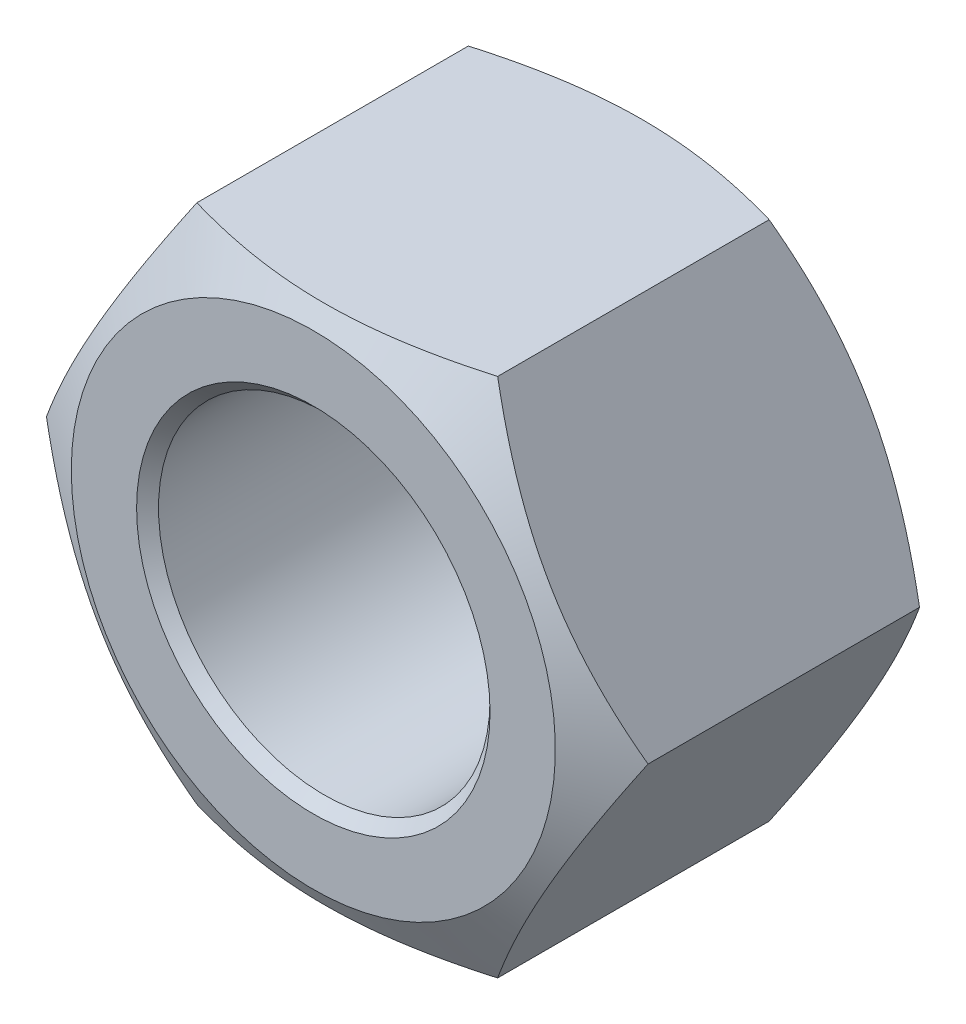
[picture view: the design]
ISO-10303-21;
HEADER;
FILE_DESCRIPTION(('STEP AP214'),'2;1');
FILE_NAME('part.step','',(''),(''),'','','');
FILE_SCHEMA(('AUTOMOTIVE_DESIGN { 1 0 10303 214 1 1 1 1 }'));
ENDSEC;
DATA;
#1=APPLICATION_CONTEXT('core data for automotive mechanical design processes');
#2=APPLICATION_PROTOCOL_DEFINITION('international standard','automotive_design',2000,#1);
#3=PRODUCT_CONTEXT('',#1,'mechanical');
#4=PRODUCT('Part','Part','',(#3));
#5=PRODUCT_RELATED_PRODUCT_CATEGORY('part','',(#4));
#6=PRODUCT_DEFINITION_FORMATION('','',#4);
#7=PRODUCT_DEFINITION_CONTEXT('part definition',#1,'design');
#8=PRODUCT_DEFINITION('design','',#6,#7);
#9=PRODUCT_DEFINITION_SHAPE('','',#8);
#10=(LENGTH_UNIT() NAMED_UNIT(*) SI_UNIT(.MILLI.,.METRE.));
#11=(NAMED_UNIT(*) PLANE_ANGLE_UNIT() SI_UNIT($,.RADIAN.));
#12=(NAMED_UNIT(*) SI_UNIT($,.STERADIAN.) SOLID_ANGLE_UNIT());
#13=UNCERTAINTY_MEASURE_WITH_UNIT(LENGTH_MEASURE(1.E-05),#10,'distance_accuracy_value','');
#14=(GEOMETRIC_REPRESENTATION_CONTEXT(3) GLOBAL_UNCERTAINTY_ASSIGNED_CONTEXT((#13)) GLOBAL_UNIT_ASSIGNED_CONTEXT((#10,
#11,#12)) REPRESENTATION_CONTEXT('',''));
#15=CARTESIAN_POINT('',(0.,0.,0.));
#16=DIRECTION('',(0.,0.,1.));
#17=DIRECTION('',(1.,0.,0.));
#18=AXIS2_PLACEMENT_3D('',#15,#16,#17);
#19=CARTESIAN_POINT('',(-15.8771324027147,-27.5,-34.7));
#20=DIRECTION('',(0.,-1.,0.));
#21=DIRECTION('',(1.,0.,0.));
#22=AXIS2_PLACEMENT_3D('',#19,#20,#21);
#23=PLANE('',#22);
#24=DIRECTION('',(0.,0.,1.));
#25=VECTOR('',#24,1.);
#26=CARTESIAN_POINT('',(15.8771324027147,-27.5,-34.7));
#27=LINE('',#26,#25);
#28=CARTESIAN_POINT('',(15.8771324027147,-27.5,-32.2437990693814));
#29=VERTEX_POINT('',#28);
#30=CARTESIAN_POINT('',(15.8771324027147,-27.5,-3.58203395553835));
#31=VERTEX_POINT('',#30);
#32=EDGE_CURVE('E149',#29,#31,#27,.T.);
#33=ORIENTED_EDGE('',*,*,#32,.T.);
#34=CARTESIAN_POINT('',(-41.9525411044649,-27.5,-14.2099719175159));
#35=CARTESIAN_POINT('',(-41.3494641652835,-27.5,-13.9187804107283));
#36=CARTESIAN_POINT('',(-40.7456533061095,-27.5,-13.6291040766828));
#37=CARTESIAN_POINT('',(-39.5364097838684,-27.5,-13.0531398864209));
#38=CARTESIAN_POINT('',(-38.9309771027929,-27.5,-12.7668520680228));
#39=CARTESIAN_POINT('',(-37.718245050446,-27.5,-12.19798059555));
#40=CARTESIAN_POINT('',(-37.1109453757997,-27.5,-11.9153975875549));
#41=CARTESIAN_POINT('',(-35.8944183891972,-27.5,-11.3544179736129));
#42=CARTESIAN_POINT('',(-35.2851910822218,-27.5,-11.0760213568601));
#43=CARTESIAN_POINT('',(-33.4472762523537,-27.5,-10.2446151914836));
#44=CARTESIAN_POINT('',(-32.2153690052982,-27.5,-9.69869201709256));
#45=CARTESIAN_POINT('',(-29.7413669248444,-27.5,-8.63048780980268));
#46=CARTESIAN_POINT('',(-28.4992726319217,-27.5,-8.10820553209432));
#47=CARTESIAN_POINT('',(-26.6196585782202,-27.5,-7.34437012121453));
#48=CARTESIAN_POINT('',(-25.9866820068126,-27.5,-7.09162545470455));
#49=CARTESIAN_POINT('',(-24.717313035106,-27.5,-6.59487593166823));
#50=CARTESIAN_POINT('',(-24.0809206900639,-27.5,-6.35087093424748));
#51=CARTESIAN_POINT('',(-22.804327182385,-27.5,-5.87272698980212));
#52=CARTESIAN_POINT('',(-22.1641254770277,-27.5,-5.63858948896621));
#53=CARTESIAN_POINT('',(-20.8797293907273,-27.5,-5.18156563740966));
#54=CARTESIAN_POINT('',(-20.2355351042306,-27.5,-4.95867902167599));
#55=CARTESIAN_POINT('',(-18.9442516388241,-27.5,-4.52613766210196));
#56=CARTESIAN_POINT('',(-18.2971717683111,-27.5,-4.31645526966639));
#57=CARTESIAN_POINT('',(-16.9985288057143,-27.5,-3.91151041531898));
#58=CARTESIAN_POINT('',(-16.3469656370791,-27.5,-3.71624820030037));
#59=CARTESIAN_POINT('',(-14.3855682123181,-27.5,-3.15498057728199));
#60=CARTESIAN_POINT('',(-13.0685242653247,-27.5,-2.81332315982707));
#61=CARTESIAN_POINT('',(-11.078834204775,-27.5,-2.36222983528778));
#62=CARTESIAN_POINT('',(-10.413074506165,-27.5,-2.22206895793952));
#63=CARTESIAN_POINT('',(-9.07715007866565,-27.5,-1.96444454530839));
#64=CARTESIAN_POINT('',(-8.40698545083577,-27.5,-1.84698049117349));
#65=CARTESIAN_POINT('',(-7.06271975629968,-27.5,-1.63684108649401));
#66=CARTESIAN_POINT('',(-6.3886184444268,-27.5,-1.54416729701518));
#67=CARTESIAN_POINT('',(-5.03726233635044,-27.5,-1.38547485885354));
#68=CARTESIAN_POINT('',(-4.36000753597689,-27.5,-1.31945624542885));
#69=CARTESIAN_POINT('',(-3.00754087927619,-27.5,-1.2158431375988));
#70=CARTESIAN_POINT('',(-2.33234242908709,-27.5,-1.17807478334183));
#71=CARTESIAN_POINT('',(-0.980955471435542,-27.5,-1.13115834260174));
#72=CARTESIAN_POINT('',(-0.30476697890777,-27.5,-1.1220098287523));
#73=CARTESIAN_POINT('',(1.04720420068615,-27.5,-1.13254920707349));
#74=CARTESIAN_POINT('',(1.72298694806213,-27.5,-1.15222928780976));
#75=CARTESIAN_POINT('',(3.07313517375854,-27.5,-1.21994143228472));
#76=CARTESIAN_POINT('',(3.7475005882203,-27.5,-1.26797474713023));
#77=CARTESIAN_POINT('',(5.38649088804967,-27.5,-1.41817622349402));
#78=CARTESIAN_POINT('',(6.34981216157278,-27.5,-1.53480225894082));
#79=CARTESIAN_POINT('',(8.26885266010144,-27.5,-1.81938601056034));
#80=CARTESIAN_POINT('',(9.22457071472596,-27.5,-1.98735147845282));
#81=CARTESIAN_POINT('',(11.1289249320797,-27.5,-2.36889784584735));
#82=CARTESIAN_POINT('',(12.0775412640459,-27.5,-2.58257679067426));
#83=CARTESIAN_POINT('',(13.9650122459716,-27.5,-3.04892276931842));
#84=CARTESIAN_POINT('',(14.9038672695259,-27.5,-3.30158830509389));
#85=CARTESIAN_POINT('',(16.7937069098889,-27.5,-3.84612374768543));
#86=CARTESIAN_POINT('',(17.7444669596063,-27.5,-4.13876776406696));
#87=CARTESIAN_POINT('',(19.6366730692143,-27.5,-4.75285886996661));
#88=CARTESIAN_POINT('',(20.5781182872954,-27.5,-5.07430853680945));
#89=CARTESIAN_POINT('',(22.4471611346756,-27.5,-5.73923774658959));
#90=CARTESIAN_POINT('',(23.374806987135,-27.5,-6.08258225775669));
#91=CARTESIAN_POINT('',(24.7604452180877,-27.5,-6.61229984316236));
#92=CARTESIAN_POINT('',(25.2212799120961,-27.5,-6.79129281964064));
#93=CARTESIAN_POINT('',(26.1411616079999,-27.5,-7.15377962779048));
#94=CARTESIAN_POINT('',(26.6002086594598,-27.5,-7.33727333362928));
#95=CARTESIAN_POINT('',(27.0584275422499,-27.5,-7.52281490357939));
#96=B_SPLINE_CURVE_WITH_KNOTS('',3,(#34,#35,#36,#37,#38,#39,#40,#41,#42,#43,#44,#45,#46,#47,#48,
#49,#50,#51,#52,#53,#54,#55,#56,#57,#58,#59,#60,#61,#62,#63,#64,#65,#66,#67,#68,#69,#70,#71,#72,
#73,#74,#75,#76,#77,#78,#79,#80,#81,#82,#83,#84,#85,#86,#87,#88,#89,#90,#91,#92,#93,#94,#95),
.UNSPECIFIED.,.F.,.F.,(4,2,2,2,2,2,2,2,2,2,2,2,2,2,2,2,2,2,2,2,2,2,2,2,2,2,2,2,2,2,4),(0.,
2.00909235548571,4.01820711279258,6.02766769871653,8.03712309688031,12.0792874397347,
16.1212386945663,18.1658995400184,20.2105274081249,22.2554539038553,24.3003322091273,
26.3407756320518,28.3812539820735,32.4606217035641,34.5013713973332,36.5420744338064,
38.5829059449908,40.6237401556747,42.651908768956,44.680047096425,46.7076359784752,
48.7353143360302,51.6447569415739,54.5546390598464,57.4708259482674,60.3869008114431,
63.3706883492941,66.3547431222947,69.3219029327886,70.8050103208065,72.288076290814),.UNSPECIFIED.);
#97=CARTESIAN_POINT('',(-15.8771324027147,-27.5,-3.58203395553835));
#98=VERTEX_POINT('',#97);
#99=EDGE_CURVE('E57',#31,#98,#96,.F.);
#100=ORIENTED_EDGE('',*,*,#99,.T.);
#101=DIRECTION('',(0.,0.,1.));
#102=VECTOR('',#101,1.);
#103=CARTESIAN_POINT('',(-15.8771324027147,-27.5,-34.7));
#104=LINE('',#103,#102);
#105=CARTESIAN_POINT('',(-15.8771324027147,-27.5,-32.2437990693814));
#106=VERTEX_POINT('',#105);
#107=EDGE_CURVE('E127',#106,#98,#104,.T.);
#108=ORIENTED_EDGE('',*,*,#107,.F.);
#109=CARTESIAN_POINT('',(-42.108494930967,-27.5,-21.5405156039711));
#110=CARTESIAN_POINT('',(-41.5048149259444,-27.5,-21.8323227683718));
#111=CARTESIAN_POINT('',(-40.9004047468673,-27.5,-22.1226241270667));
#112=CARTESIAN_POINT('',(-39.6899708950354,-27.5,-22.6998596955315));
#113=CARTESIAN_POINT('',(-39.0839472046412,-27.5,-22.9867938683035));
#114=CARTESIAN_POINT('',(-37.8700434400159,-27.5,-23.5569814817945));
#115=CARTESIAN_POINT('',(-37.2621630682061,-27.5,-23.840234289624));
#116=CARTESIAN_POINT('',(-36.0444843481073,-27.5,-24.4025807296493));
#117=CARTESIAN_POINT('',(-35.4346860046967,-27.5,-24.6816743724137));
#118=CARTESIAN_POINT('',(-33.5951504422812,-27.5,-25.5151881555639));
#119=CARTESIAN_POINT('',(-32.3622101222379,-27.5,-26.0625698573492));
#120=CARTESIAN_POINT('',(-29.8861914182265,-27.5,-27.1338541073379));
#121=CARTESIAN_POINT('',(-28.6431135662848,-27.5,-27.6577578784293));
#122=CARTESIAN_POINT('',(-26.761690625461,-27.5,-28.4243433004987));
#123=CARTESIAN_POINT('',(-26.1278670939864,-27.5,-28.6781337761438));
#124=CARTESIAN_POINT('',(-24.856813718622,-27.5,-29.177025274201));
#125=CARTESIAN_POINT('',(-24.2195839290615,-27.5,-29.4221264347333));
#126=CARTESIAN_POINT('',(-22.9413245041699,-27.5,-29.9025185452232));
#127=CARTESIAN_POINT('',(-22.3002943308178,-27.5,-30.1378080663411));
#128=CARTESIAN_POINT('',(-21.0142476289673,-27.5,-30.5971975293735));
#129=CARTESIAN_POINT('',(-20.3692311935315,-27.5,-30.8212977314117));
#130=CARTESIAN_POINT('',(-19.0762913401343,-27.5,-31.256336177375));
#131=CARTESIAN_POINT('',(-18.4283771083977,-27.5,-31.4673015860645));
#132=CARTESIAN_POINT('',(-17.1280636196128,-27.5,-31.874881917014));
#133=CARTESIAN_POINT('',(-16.4756642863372,-27.5,-32.0714965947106));
#134=CARTESIAN_POINT('',(-14.5117448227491,-27.5,-32.6369304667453));
#135=CARTESIAN_POINT('',(-13.1930050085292,-27.5,-32.9815100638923));
#136=CARTESIAN_POINT('',(-11.2007577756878,-27.5,-33.4371656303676));
#137=CARTESIAN_POINT('',(-10.5341776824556,-27.5,-33.5788718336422));
#138=CARTESIAN_POINT('',(-9.19657522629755,-27.5,-33.8396423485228));
#139=CARTESIAN_POINT('',(-8.52555296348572,-27.5,-33.9587071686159));
#140=CARTESIAN_POINT('',(-7.17952384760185,-27.5,-34.1720839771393));
#141=CARTESIAN_POINT('',(-6.50451675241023,-27.5,-34.2663944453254));
#142=CARTESIAN_POINT('',(-5.15128946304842,-27.5,-34.4283683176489));
#143=CARTESIAN_POINT('',(-4.47306926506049,-27.5,-34.4960316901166));
#144=CARTESIAN_POINT('',(-3.11871087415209,-27.5,-34.6028897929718));
#145=CARTESIAN_POINT('',(-2.44258682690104,-27.5,-34.6422626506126));
#146=CARTESIAN_POINT('',(-1.08928096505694,-27.5,-34.6923327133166));
#147=CARTESIAN_POINT('',(-0.412099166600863,-27.5,-34.7030303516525));
#148=CARTESIAN_POINT('',(0.941918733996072,-27.5,-34.6954963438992));
#149=CARTESIAN_POINT('',(1.61875487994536,-27.5,-34.6772727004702));
#150=CARTESIAN_POINT('',(2.97106504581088,-27.5,-34.6123489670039));
#151=CARTESIAN_POINT('',(3.64653900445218,-27.5,-34.5656476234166));
#152=CARTESIAN_POINT('',(5.28317631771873,-27.5,-34.4189661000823));
#153=CARTESIAN_POINT('',(6.24308439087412,-27.5,-34.3047469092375));
#154=CARTESIAN_POINT('',(8.15543073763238,-27.5,-34.0251507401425));
#155=CARTESIAN_POINT('',(9.10786788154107,-27.5,-33.8597661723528));
#156=CARTESIAN_POINT('',(11.0057578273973,-27.5,-33.4834652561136));
#157=CARTESIAN_POINT('',(11.9511910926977,-27.5,-33.2724513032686));
#158=CARTESIAN_POINT('',(13.8323781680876,-27.5,-32.8114440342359));
#159=CARTESIAN_POINT('',(14.7681323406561,-27.5,-32.5614521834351));
#160=CARTESIAN_POINT('',(16.6519981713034,-27.5,-32.0222222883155));
#161=CARTESIAN_POINT('',(17.5998839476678,-27.5,-31.7322004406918));
#162=CARTESIAN_POINT('',(19.4863693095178,-27.5,-31.1232820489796));
#163=CARTESIAN_POINT('',(20.4249680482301,-27.5,-30.8043828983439));
#164=CARTESIAN_POINT('',(22.2883658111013,-27.5,-30.1444557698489));
#165=CARTESIAN_POINT('',(23.2132128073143,-27.5,-29.8035627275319));
#166=CARTESIAN_POINT('',(24.5946517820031,-27.5,-29.2774659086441));
#167=CARTESIAN_POINT('',(25.054086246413,-27.5,-29.0996704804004));
#168=CARTESIAN_POINT('',(25.9711665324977,-27.5,-28.7395606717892));
#169=CARTESIAN_POINT('',(26.4288124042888,-27.5,-28.5572464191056));
#170=CARTESIAN_POINT('',(26.8856293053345,-27.5,-28.3728755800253));
#171=B_SPLINE_CURVE_WITH_KNOTS('',3,(#109,#110,#111,#112,#113,#114,#115,#116,#117,#118,#119,
#120,#121,#122,#123,#124,#125,#126,#127,#128,#129,#130,#131,#132,#133,#134,#135,#136,#137,#138,
#139,#140,#141,#142,#143,#144,#145,#146,#147,#148,#149,#150,#151,#152,#153,#154,#155,#156,#157,
#158,#159,#160,#161,#162,#163,#164,#165,#166,#167,#168,#169,#170),.UNSPECIFIED.,.F.,.F.,(4,2,2,
2,2,2,2,2,2,2,2,2,2,2,2,2,2,2,2,2,2,2,2,2,2,2,2,2,2,2,4),(0.,2.01152483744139,4.02307175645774,
6.034960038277,8.0468432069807,12.0936174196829,16.1401806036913,18.1883662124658,
20.2365192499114,22.2849695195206,24.3333721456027,26.3773870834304,28.42143684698,
32.5079579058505,34.5520769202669,36.596150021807,38.6403486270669,40.6845496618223,
42.7157641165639,44.7469478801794,46.7775697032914,48.808280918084,51.7067063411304,
54.6055619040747,57.5106807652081,60.4156904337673,63.3889230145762,66.3624242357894,
69.3191566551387,70.7970485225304,72.2748986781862),.UNSPECIFIED.);
#172=CARTESIAN_POINT('',(0.,-27.5,-34.7));
#173=VERTEX_POINT('',#172);
#174=EDGE_CURVE('E313',#106,#173,#171,.T.);
#175=ORIENTED_EDGE('',*,*,#174,.T.);
#176=EDGE_CURVE('E174',#173,#29,#171,.T.);
#177=ORIENTED_EDGE('',*,*,#176,.T.);
#178=EDGE_LOOP('',(#33,#100,#108,#175,#177));
#179=FACE_BOUND('',#178,.T.);
#180=ADVANCED_FACE('F41',(#179),#23,.T.);
#181=CARTESIAN_POINT('',(-31.7542648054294,0.,-34.7));
#182=DIRECTION('',(-0.866025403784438,-0.5,0.));
#183=DIRECTION('',(0.5,-0.866025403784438,0.));
#184=AXIS2_PLACEMENT_3D('',#181,#182,#183);
#185=PLANE('',#184);
#186=ORIENTED_EDGE('',*,*,#107,.T.);
#187=CARTESIAN_POINT('',(-15.8770169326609,-27.5002,-3.58210062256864));
#188=CARTESIAN_POINT('',(-16.2259892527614,-26.8957622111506,-3.38063638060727));
#189=CARTESIAN_POINT('',(-16.5763227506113,-26.2889667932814,-3.1883143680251));
#190=CARTESIAN_POINT('',(-17.2797989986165,-25.0705101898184,-2.82449599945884));
#191=CARTESIAN_POINT('',(-17.6329426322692,-24.4588474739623,-2.65300649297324));
#192=CARTESIAN_POINT('',(-18.3427291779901,-23.229461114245,-2.33315493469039));
#193=CARTESIAN_POINT('',(-18.6993783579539,-22.6117266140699,-2.18484811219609));
#194=CARTESIAN_POINT('',(-19.4151397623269,-21.371991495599,-1.91455679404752));
#195=CARTESIAN_POINT('',(-19.7742517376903,-20.7499913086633,-1.79256967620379));
#196=CARTESIAN_POINT('',(-20.4857595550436,-19.5176236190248,-1.58009593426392));
#197=CARTESIAN_POINT('',(-20.8381026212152,-18.907347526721,-1.48890665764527));
#198=CARTESIAN_POINT('',(-21.5444032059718,-17.683999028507,-1.33600321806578));
#199=CARTESIAN_POINT('',(-21.8983607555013,-17.0709265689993,-1.27428962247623));
#200=CARTESIAN_POINT('',(-22.6068704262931,-15.8437518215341,-1.181895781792));
#201=CARTESIAN_POINT('',(-22.9614213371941,-15.2296516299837,-1.15117866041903));
#202=CARTESIAN_POINT('',(-23.6708503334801,-14.0008845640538,-1.12143833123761));
#203=CARTESIAN_POINT('',(-24.025728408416,-13.3862177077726,-1.12241414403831));
#204=CARTESIAN_POINT('',(-24.6891773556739,-12.2370904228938,-1.15384594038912));
#205=CARTESIAN_POINT('',(-24.9977954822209,-11.7025481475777,-1.180469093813));
#206=CARTESIAN_POINT('',(-25.6142949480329,-10.6347397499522,-1.25717911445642));
#207=CARTESIAN_POINT('',(-25.9221762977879,-10.1014736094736,-1.30726564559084));
#208=CARTESIAN_POINT('',(-26.5370884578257,-9.03641450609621,-1.43003437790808));
#209=CARTESIAN_POINT('',(-26.8441182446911,-8.50462331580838,-1.50273701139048));
#210=CARTESIAN_POINT('',(-27.4567077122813,-7.44358723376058,-1.6694512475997));
#211=CARTESIAN_POINT('',(-27.7622673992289,-6.9143423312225,-1.76346276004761));
#212=CARTESIAN_POINT('',(-28.6898814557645,-5.30766765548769,-2.07987326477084));
#213=CARTESIAN_POINT('',(-29.3093003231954,-4.23480270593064,-2.33383899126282));
#214=CARTESIAN_POINT('',(-30.2315881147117,-2.63735339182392,-2.76620358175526));
#215=CARTESIAN_POINT('',(-30.5376130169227,-2.10730271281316,-2.91873886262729));
#216=CARTESIAN_POINT('',(-31.1475461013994,-1.05086762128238,-3.23925171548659));
#217=CARTESIAN_POINT('',(-31.4514548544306,-0.524482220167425,-3.40722493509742));
#218=CARTESIAN_POINT('',(-31.7543802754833,0.000199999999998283,-3.58210062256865));
#219=B_SPLINE_CURVE_WITH_KNOTS('',3,(#187,#188,#189,#190,#191,#192,#193,#194,#195,#196,#197,
#198,#199,#200,#201,#202,#203,#204,#205,#206,#207,#208,#209,#210,#211,#212,#213,#214,#215,#216,
#217,#218),.UNSPECIFIED.,.F.,.F.,(4,2,2,2,2,2,2,2,2,2,2,2,2,2,2,4),(0.,2.17937596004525,
4.35946654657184,6.54467421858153,8.72966408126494,10.8607692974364,12.9919155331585,
15.120523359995,17.2490654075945,19.1020483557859,20.9550047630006,22.8096400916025,
24.6642675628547,28.4552152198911,30.3473870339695,32.2390270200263),.UNSPECIFIED.);
#220=CARTESIAN_POINT('',(-31.7542648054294,0.,-3.58203395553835));
#221=VERTEX_POINT('',#220);
#222=EDGE_CURVE('E112',#98,#221,#219,.T.);
#223=ORIENTED_EDGE('',*,*,#222,.T.);
#224=DIRECTION('',(0.,0.,1.));
#225=VECTOR('',#224,1.);
#226=CARTESIAN_POINT('',(-31.7542648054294,0.,-34.7));
#227=LINE('',#226,#225);
#228=CARTESIAN_POINT('',(-31.7542648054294,0.,-32.2437990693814));
#229=VERTEX_POINT('',#228);
#230=EDGE_CURVE('E130',#229,#221,#227,.T.);
#231=ORIENTED_EDGE('',*,*,#230,.F.);
#232=CARTESIAN_POINT('',(-31.7543802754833,0.000200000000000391,-32.2437324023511));
#233=CARTESIAN_POINT('',(-31.4054079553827,-0.604237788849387,-32.4451966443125));
#234=CARTESIAN_POINT('',(-31.0550744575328,-1.21103320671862,-32.6375186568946));
#235=CARTESIAN_POINT('',(-30.3515982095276,-2.42948981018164,-33.0013370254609));
#236=CARTESIAN_POINT('',(-29.9984545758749,-3.04115252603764,-33.1728265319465));
#237=CARTESIAN_POINT('',(-29.288668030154,-4.27053888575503,-33.4926780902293));
#238=CARTESIAN_POINT('',(-28.9320188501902,-4.88827338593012,-33.6409849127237));
#239=CARTESIAN_POINT('',(-28.2162574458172,-6.12800850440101,-33.9112762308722));
#240=CARTESIAN_POINT('',(-27.8571454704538,-6.75000869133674,-34.033263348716));
#241=CARTESIAN_POINT('',(-27.1456376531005,-7.98237638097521,-34.2457370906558));
#242=CARTESIAN_POINT('',(-26.7932945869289,-8.59265247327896,-34.3369263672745));
#243=CARTESIAN_POINT('',(-26.0869940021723,-9.81600097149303,-34.489829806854));
#244=CARTESIAN_POINT('',(-25.7330364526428,-10.4290734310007,-34.5515434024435));
#245=CARTESIAN_POINT('',(-25.024526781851,-11.6562481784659,-34.6439372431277));
#246=CARTESIAN_POINT('',(-24.66997587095,-12.2703483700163,-34.6746543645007));
#247=CARTESIAN_POINT('',(-23.960546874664,-13.4991154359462,-34.7043946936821));
#248=CARTESIAN_POINT('',(-23.6056687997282,-14.1137822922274,-34.7034188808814));
#249=CARTESIAN_POINT('',(-22.9422198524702,-15.2629095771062,-34.6719870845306));
#250=CARTESIAN_POINT('',(-22.6336017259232,-15.7974518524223,-34.6453639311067));
#251=CARTESIAN_POINT('',(-22.0171022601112,-16.8652602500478,-34.5686539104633));
#252=CARTESIAN_POINT('',(-21.7092209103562,-17.3985263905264,-34.5185673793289));
#253=CARTESIAN_POINT('',(-21.0943087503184,-18.4635854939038,-34.3957986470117));
#254=CARTESIAN_POINT('',(-20.787278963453,-18.9953766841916,-34.3230960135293));
#255=CARTESIAN_POINT('',(-20.1746894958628,-20.0564127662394,-34.15638177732));
#256=CARTESIAN_POINT('',(-19.8691298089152,-20.5856576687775,-34.0623702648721));
#257=CARTESIAN_POINT('',(-18.9415157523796,-22.1923323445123,-33.7459597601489));
#258=CARTESIAN_POINT('',(-18.3220968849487,-23.2651972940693,-33.4919940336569));
#259=CARTESIAN_POINT('',(-17.3998090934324,-24.8626466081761,-33.0596294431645));
#260=CARTESIAN_POINT('',(-17.0937841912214,-25.3926972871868,-32.9070941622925));
#261=CARTESIAN_POINT('',(-16.4838511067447,-26.4491323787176,-32.5865813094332));
#262=CARTESIAN_POINT('',(-16.1799423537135,-26.9755177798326,-32.4186080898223));
#263=CARTESIAN_POINT('',(-15.8770169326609,-27.5002,-32.2437324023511));
#264=B_SPLINE_CURVE_WITH_KNOTS('',3,(#232,#233,#234,#235,#236,#237,#238,#239,#240,#241,#242,
#243,#244,#245,#246,#247,#248,#249,#250,#251,#252,#253,#254,#255,#256,#257,#258,#259,#260,#261,
#262,#263),.UNSPECIFIED.,.F.,.F.,(4,2,2,2,2,2,2,2,2,2,2,2,2,2,2,4),(0.,2.17937596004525,
4.35946654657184,6.54467421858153,8.72966408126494,10.8607692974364,12.9919155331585,
15.120523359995,17.2490654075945,19.1020483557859,20.9550047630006,22.8096400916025,
24.6642675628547,28.4552152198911,30.3473870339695,32.2390270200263),.UNSPECIFIED.);
#265=CARTESIAN_POINT('',(-23.815698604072,-13.75,-34.7));
#266=VERTEX_POINT('',#265);
#267=EDGE_CURVE('E245',#229,#266,#264,.T.);
#268=ORIENTED_EDGE('',*,*,#267,.T.);
#269=EDGE_CURVE('E236',#266,#106,#264,.T.);
#270=ORIENTED_EDGE('',*,*,#269,.T.);
#271=EDGE_LOOP('',(#186,#223,#231,#268,#270));
#272=FACE_BOUND('',#271,.T.);
#273=ADVANCED_FACE('F123',(#272),#185,.T.);
#274=CARTESIAN_POINT('',(-15.8771324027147,27.5,-34.7));
#275=DIRECTION('',(-0.866025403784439,0.5,0.));
#276=DIRECTION('',(-0.5,-0.866025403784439,0.));
#277=AXIS2_PLACEMENT_3D('',#274,#275,#276);
#278=PLANE('',#277);
#279=ORIENTED_EDGE('',*,*,#230,.T.);
#280=CARTESIAN_POINT('',(-31.7543802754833,-0.000199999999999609,-3.58210062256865));
#281=CARTESIAN_POINT('',(-31.4054079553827,0.604237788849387,-3.38063638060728));
#282=CARTESIAN_POINT('',(-31.0550744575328,1.21103320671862,-3.18831436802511));
#283=CARTESIAN_POINT('',(-30.3515982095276,2.42948981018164,-2.82449599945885));
#284=CARTESIAN_POINT('',(-29.9984545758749,3.04115252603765,-2.65300649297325));
#285=CARTESIAN_POINT('',(-29.288668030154,4.27053888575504,-2.3331549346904));
#286=CARTESIAN_POINT('',(-28.9320188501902,4.88827338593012,-2.18484811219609));
#287=CARTESIAN_POINT('',(-28.2162574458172,6.12800850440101,-1.91455679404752));
#288=CARTESIAN_POINT('',(-27.8571454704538,6.75000869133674,-1.79256967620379));
#289=CARTESIAN_POINT('',(-27.1456376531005,7.98237638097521,-1.58009593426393));
#290=CARTESIAN_POINT('',(-26.7932945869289,8.59265247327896,-1.48890665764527));
#291=CARTESIAN_POINT('',(-26.0869940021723,9.81600097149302,-1.33600321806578));
#292=CARTESIAN_POINT('',(-25.7330364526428,10.4290734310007,-1.27428962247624));
#293=CARTESIAN_POINT('',(-25.024526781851,11.6562481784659,-1.181895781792));
#294=CARTESIAN_POINT('',(-24.66997587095,12.2703483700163,-1.15117866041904));
#295=CARTESIAN_POINT('',(-23.960546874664,13.4991154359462,-1.12143833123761));
#296=CARTESIAN_POINT('',(-23.6056687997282,14.1137822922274,-1.12241414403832));
#297=CARTESIAN_POINT('',(-22.9422198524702,15.2629095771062,-1.15384594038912));
#298=CARTESIAN_POINT('',(-22.6336017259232,15.7974518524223,-1.180469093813));
#299=CARTESIAN_POINT('',(-22.0171022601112,16.8652602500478,-1.25717911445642));
#300=CARTESIAN_POINT('',(-21.7092209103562,17.3985263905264,-1.30726564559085));
#301=CARTESIAN_POINT('',(-21.0943087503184,18.4635854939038,-1.43003437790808));
#302=CARTESIAN_POINT('',(-20.787278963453,18.9953766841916,-1.50273701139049));
#303=CARTESIAN_POINT('',(-20.1746894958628,20.0564127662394,-1.6694512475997));
#304=CARTESIAN_POINT('',(-19.8691298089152,20.5856576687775,-1.76346276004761));
#305=CARTESIAN_POINT('',(-18.9415157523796,22.1923323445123,-2.07987326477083));
#306=CARTESIAN_POINT('',(-18.3220968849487,23.2651972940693,-2.33383899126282));
#307=CARTESIAN_POINT('',(-17.3998090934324,24.8626466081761,-2.76620358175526));
#308=CARTESIAN_POINT('',(-17.0937841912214,25.3926972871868,-2.91873886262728));
#309=CARTESIAN_POINT('',(-16.4838511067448,26.4491323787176,-3.23925171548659));
#310=CARTESIAN_POINT('',(-16.1799423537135,26.9755177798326,-3.40722493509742));
#311=CARTESIAN_POINT('',(-15.8770169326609,27.5002,-3.58210062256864));
#312=B_SPLINE_CURVE_WITH_KNOTS('',3,(#280,#281,#282,#283,#284,#285,#286,#287,#288,#289,#290,
#291,#292,#293,#294,#295,#296,#297,#298,#299,#300,#301,#302,#303,#304,#305,#306,#307,#308,#309,
#310,#311),.UNSPECIFIED.,.F.,.F.,(4,2,2,2,2,2,2,2,2,2,2,2,2,2,2,4),(0.,2.17937596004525,
4.35946654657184,6.54467421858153,8.72966408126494,10.8607692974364,12.9919155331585,
15.120523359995,17.2490654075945,19.1020483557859,20.9550047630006,22.8096400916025,
24.6642675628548,28.4552152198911,30.3473870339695,32.2390270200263),.UNSPECIFIED.);
#313=CARTESIAN_POINT('',(-15.8771324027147,27.5,-3.58203395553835));
#314=VERTEX_POINT('',#313);
#315=EDGE_CURVE('E111',#221,#314,#312,.T.);
#316=ORIENTED_EDGE('',*,*,#315,.T.);
#317=DIRECTION('',(0.,0.,1.));
#318=VECTOR('',#317,1.);
#319=CARTESIAN_POINT('',(-15.8771324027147,27.5,-34.7));
#320=LINE('',#319,#318);
#321=CARTESIAN_POINT('',(-15.8771324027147,27.5,-32.2437990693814));
#322=VERTEX_POINT('',#321);
#323=EDGE_CURVE('E138',#322,#314,#320,.T.);
#324=ORIENTED_EDGE('',*,*,#323,.F.);
#325=CARTESIAN_POINT('',(-15.8770169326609,27.5002,-32.2437324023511));
#326=CARTESIAN_POINT('',(-16.2259892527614,26.8957622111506,-32.4451966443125));
#327=CARTESIAN_POINT('',(-16.5763227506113,26.2889667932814,-32.6375186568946));
#328=CARTESIAN_POINT('',(-17.2797989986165,25.0705101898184,-33.0013370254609));
#329=CARTESIAN_POINT('',(-17.6329426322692,24.4588474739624,-33.1728265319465));
#330=CARTESIAN_POINT('',(-18.3427291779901,23.229461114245,-33.4926780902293));
#331=CARTESIAN_POINT('',(-18.6993783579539,22.6117266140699,-33.6409849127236));
#332=CARTESIAN_POINT('',(-19.4151397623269,21.371991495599,-33.9112762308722));
#333=CARTESIAN_POINT('',(-19.7742517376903,20.7499913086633,-34.033263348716));
#334=CARTESIAN_POINT('',(-20.4857595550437,19.5176236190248,-34.2457370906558));
#335=CARTESIAN_POINT('',(-20.8381026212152,18.907347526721,-34.3369263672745));
#336=CARTESIAN_POINT('',(-21.5444032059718,17.683999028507,-34.489829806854));
#337=CARTESIAN_POINT('',(-21.8983607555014,17.0709265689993,-34.5515434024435));
#338=CARTESIAN_POINT('',(-22.6068704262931,15.8437518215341,-34.6439372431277));
#339=CARTESIAN_POINT('',(-22.9614213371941,15.2296516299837,-34.6746543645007));
#340=CARTESIAN_POINT('',(-23.6708503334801,14.0008845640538,-34.7043946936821));
#341=CARTESIAN_POINT('',(-24.025728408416,13.3862177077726,-34.7034188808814));
#342=CARTESIAN_POINT('',(-24.6891773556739,12.2370904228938,-34.6719870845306));
#343=CARTESIAN_POINT('',(-24.9977954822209,11.7025481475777,-34.6453639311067));
#344=CARTESIAN_POINT('',(-25.6142949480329,10.6347397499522,-34.5686539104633));
#345=CARTESIAN_POINT('',(-25.9221762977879,10.1014736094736,-34.5185673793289));
#346=CARTESIAN_POINT('',(-26.5370884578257,9.03641450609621,-34.3957986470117));
#347=CARTESIAN_POINT('',(-26.8441182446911,8.50462331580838,-34.3230960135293));
#348=CARTESIAN_POINT('',(-27.4567077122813,7.44358723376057,-34.15638177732));
#349=CARTESIAN_POINT('',(-27.7622673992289,6.91434233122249,-34.0623702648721));
#350=CARTESIAN_POINT('',(-28.6898814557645,5.3076676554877,-33.7459597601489));
#351=CARTESIAN_POINT('',(-29.3093003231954,4.23480270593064,-33.4919940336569));
#352=CARTESIAN_POINT('',(-30.2315881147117,2.63735339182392,-33.0596294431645));
#353=CARTESIAN_POINT('',(-30.5376130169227,2.10730271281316,-32.9070941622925));
#354=CARTESIAN_POINT('',(-31.1475461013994,1.05086762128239,-32.5865813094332));
#355=CARTESIAN_POINT('',(-31.4514548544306,0.524482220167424,-32.4186080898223));
#356=CARTESIAN_POINT('',(-31.7543802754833,-0.000199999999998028,-32.2437324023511));
#357=B_SPLINE_CURVE_WITH_KNOTS('',3,(#325,#326,#327,#328,#329,#330,#331,#332,#333,#334,#335,
#336,#337,#338,#339,#340,#341,#342,#343,#344,#345,#346,#347,#348,#349,#350,#351,#352,#353,#354,
#355,#356),.UNSPECIFIED.,.F.,.F.,(4,2,2,2,2,2,2,2,2,2,2,2,2,2,2,4),(0.,2.17937596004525,
4.35946654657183,6.54467421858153,8.72966408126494,10.8607692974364,12.9919155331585,
15.120523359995,17.2490654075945,19.1020483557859,20.9550047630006,22.8096400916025,
24.6642675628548,28.4552152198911,30.3473870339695,32.2390270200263),.UNSPECIFIED.);
#358=CARTESIAN_POINT('',(-23.8156986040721,13.75,-34.7));
#359=VERTEX_POINT('',#358);
#360=EDGE_CURVE('E154',#322,#359,#357,.T.);
#361=ORIENTED_EDGE('',*,*,#360,.T.);
#362=EDGE_CURVE('E133',#359,#229,#357,.T.);
#363=ORIENTED_EDGE('',*,*,#362,.T.);
#364=EDGE_LOOP('',(#279,#316,#324,#361,#363));
#365=FACE_BOUND('',#364,.T.);
#366=ADVANCED_FACE('F135',(#365),#278,.T.);
#367=CARTESIAN_POINT('',(15.8771324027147,27.5,-34.7));
#368=DIRECTION('',(0.,1.,0.));
#369=DIRECTION('',(0.,0.,1.));
#370=AXIS2_PLACEMENT_3D('',#367,#368,#369);
#371=PLANE('',#370);
#372=ORIENTED_EDGE('',*,*,#323,.T.);
#373=CARTESIAN_POINT('',(-41.9525411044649,27.5,-14.2099719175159));
#374=CARTESIAN_POINT('',(-41.3494641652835,27.5,-13.9187804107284));
#375=CARTESIAN_POINT('',(-40.7456533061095,27.5,-13.6291040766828));
#376=CARTESIAN_POINT('',(-39.5364097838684,27.5,-13.0531398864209));
#377=CARTESIAN_POINT('',(-38.9309771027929,27.5,-12.7668520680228));
#378=CARTESIAN_POINT('',(-37.718245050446,27.5,-12.19798059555));
#379=CARTESIAN_POINT('',(-37.1109453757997,27.5,-11.9153975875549));
#380=CARTESIAN_POINT('',(-35.8944183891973,27.5,-11.3544179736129));
#381=CARTESIAN_POINT('',(-35.2851910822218,27.5,-11.0760213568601));
#382=CARTESIAN_POINT('',(-33.4472762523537,27.5,-10.2446151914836));
#383=CARTESIAN_POINT('',(-32.2153690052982,27.5,-9.69869201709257));
#384=CARTESIAN_POINT('',(-29.7413669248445,27.5,-8.63048780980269));
#385=CARTESIAN_POINT('',(-28.4992726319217,27.5,-8.10820553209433));
#386=CARTESIAN_POINT('',(-26.6196585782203,27.5,-7.34437012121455));
#387=CARTESIAN_POINT('',(-25.9866820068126,27.5,-7.09162545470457));
#388=CARTESIAN_POINT('',(-24.717313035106,27.5,-6.59487593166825));
#389=CARTESIAN_POINT('',(-24.080920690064,27.5,-6.35087093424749));
#390=CARTESIAN_POINT('',(-22.804327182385,27.5,-5.87272698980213));
#391=CARTESIAN_POINT('',(-22.1641254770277,27.5,-5.63858948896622));
#392=CARTESIAN_POINT('',(-20.8797293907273,27.5,-5.18156563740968));
#393=CARTESIAN_POINT('',(-20.2355351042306,27.5,-4.958679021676));
#394=CARTESIAN_POINT('',(-18.9442516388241,27.5,-4.52613766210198));
#395=CARTESIAN_POINT('',(-18.2971717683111,27.5,-4.3164552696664));
#396=CARTESIAN_POINT('',(-16.9985288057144,27.5,-3.91151041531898));
#397=CARTESIAN_POINT('',(-16.3469656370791,27.5,-3.71624820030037));
#398=CARTESIAN_POINT('',(-14.3855682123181,27.5,-3.154980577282));
#399=CARTESIAN_POINT('',(-13.0685242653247,27.5,-2.81332315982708));
#400=CARTESIAN_POINT('',(-11.078834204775,27.5,-2.36222983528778));
#401=CARTESIAN_POINT('',(-10.413074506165,27.5,-2.22206895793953));
#402=CARTESIAN_POINT('',(-9.07715007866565,27.5,-1.96444454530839));
#403=CARTESIAN_POINT('',(-8.40698545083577,27.5,-1.84698049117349));
#404=CARTESIAN_POINT('',(-7.06271975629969,27.5,-1.63684108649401));
#405=CARTESIAN_POINT('',(-6.3886184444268,27.5,-1.54416729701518));
#406=CARTESIAN_POINT('',(-5.03726233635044,27.5,-1.38547485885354));
#407=CARTESIAN_POINT('',(-4.36000753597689,27.5,-1.31945624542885));
#408=CARTESIAN_POINT('',(-3.00754087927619,27.5,-1.2158431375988));
#409=CARTESIAN_POINT('',(-2.33234242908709,27.5,-1.17807478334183));
#410=CARTESIAN_POINT('',(-0.980955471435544,27.5,-1.13115834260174));
#411=CARTESIAN_POINT('',(-0.304766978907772,27.5,-1.1220098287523));
#412=CARTESIAN_POINT('',(1.04720420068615,27.5,-1.13254920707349));
#413=CARTESIAN_POINT('',(1.72298694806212,27.5,-1.15222928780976));
#414=CARTESIAN_POINT('',(3.07313517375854,27.5,-1.21994143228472));
#415=CARTESIAN_POINT('',(3.74750058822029,27.5,-1.26797474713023));
#416=CARTESIAN_POINT('',(5.38649088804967,27.5,-1.41817622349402));
#417=CARTESIAN_POINT('',(6.34981216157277,27.5,-1.53480225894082));
#418=CARTESIAN_POINT('',(8.26885266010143,27.5,-1.81938601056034));
#419=CARTESIAN_POINT('',(9.22457071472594,27.5,-1.98735147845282));
#420=CARTESIAN_POINT('',(11.1289249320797,27.5,-2.36889784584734));
#421=CARTESIAN_POINT('',(12.0775412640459,27.5,-2.58257679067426));
#422=CARTESIAN_POINT('',(13.9650122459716,27.5,-3.04892276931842));
#423=CARTESIAN_POINT('',(14.9038672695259,27.5,-3.30158830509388));
#424=CARTESIAN_POINT('',(16.7937069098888,27.5,-3.84612374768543));
#425=CARTESIAN_POINT('',(17.7444669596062,27.5,-4.13876776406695));
#426=CARTESIAN_POINT('',(19.6366730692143,27.5,-4.75285886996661));
#427=CARTESIAN_POINT('',(20.5781182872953,27.5,-5.07430853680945));
#428=CARTESIAN_POINT('',(22.4471611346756,27.5,-5.73923774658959));
#429=CARTESIAN_POINT('',(23.374806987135,27.5,-6.08258225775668));
#430=CARTESIAN_POINT('',(24.7604452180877,27.5,-6.61229984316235));
#431=CARTESIAN_POINT('',(25.2212799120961,27.5,-6.79129281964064));
#432=CARTESIAN_POINT('',(26.1411616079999,27.5,-7.15377962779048));
#433=CARTESIAN_POINT('',(26.6002086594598,27.5,-7.33727333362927));
#434=CARTESIAN_POINT('',(27.0584275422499,27.5,-7.52281490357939));
#435=B_SPLINE_CURVE_WITH_KNOTS('',3,(#373,#374,#375,#376,#377,#378,#379,#380,#381,#382,#383,
#384,#385,#386,#387,#388,#389,#390,#391,#392,#393,#394,#395,#396,#397,#398,#399,#400,#401,#402,
#403,#404,#405,#406,#407,#408,#409,#410,#411,#412,#413,#414,#415,#416,#417,#418,#419,#420,#421,
#422,#423,#424,#425,#426,#427,#428,#429,#430,#431,#432,#433,#434),.UNSPECIFIED.,.F.,.F.,(4,2,2,
2,2,2,2,2,2,2,2,2,2,2,2,2,2,2,2,2,2,2,2,2,2,2,2,2,2,2,4),(0.,2.0090923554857,4.01820711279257,
6.02766769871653,8.03712309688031,12.0792874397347,16.1212386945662,18.1658995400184,
20.2105274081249,22.2554539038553,24.3003322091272,26.3407756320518,28.3812539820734,
32.4606217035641,34.5013713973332,36.5420744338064,38.5829059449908,40.6237401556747,
42.651908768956,44.680047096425,46.7076359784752,48.7353143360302,51.6447569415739,
54.5546390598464,57.4708259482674,60.3869008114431,63.3706883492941,66.3547431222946,
69.3219029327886,70.8050103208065,72.288076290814),.UNSPECIFIED.);
#436=CARTESIAN_POINT('',(15.8771324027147,27.5,-3.58203395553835));
#437=VERTEX_POINT('',#436);
#438=EDGE_CURVE('E116',#314,#437,#435,.T.);
#439=ORIENTED_EDGE('',*,*,#438,.T.);
#440=DIRECTION('',(0.,0.,1.));
#441=VECTOR('',#440,1.);
#442=CARTESIAN_POINT('',(15.8771324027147,27.5,-34.7));
#443=LINE('',#442,#441);
#444=CARTESIAN_POINT('',(15.8771324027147,27.5,-32.2437990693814));
#445=VERTEX_POINT('',#444);
#446=EDGE_CURVE('E136',#445,#437,#443,.T.);
#447=ORIENTED_EDGE('',*,*,#446,.F.);
#448=CARTESIAN_POINT('',(-42.108494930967,27.5,-21.5405156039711));
#449=CARTESIAN_POINT('',(-41.5048149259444,27.5,-21.8323227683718));
#450=CARTESIAN_POINT('',(-40.9004047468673,27.5,-22.1226241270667));
#451=CARTESIAN_POINT('',(-39.6899708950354,27.5,-22.6998596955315));
#452=CARTESIAN_POINT('',(-39.0839472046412,27.5,-22.9867938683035));
#453=CARTESIAN_POINT('',(-37.870043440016,27.5,-23.5569814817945));
#454=CARTESIAN_POINT('',(-37.2621630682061,27.5,-23.8402342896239));
#455=CARTESIAN_POINT('',(-36.0444843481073,27.5,-24.4025807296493));
#456=CARTESIAN_POINT('',(-35.4346860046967,27.5,-24.6816743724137));
#457=CARTESIAN_POINT('',(-33.5951504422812,27.5,-25.5151881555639));
#458=CARTESIAN_POINT('',(-32.3622101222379,27.5,-26.0625698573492));
#459=CARTESIAN_POINT('',(-29.8861914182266,27.5,-27.1338541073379));
#460=CARTESIAN_POINT('',(-28.6431135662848,27.5,-27.6577578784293));
#461=CARTESIAN_POINT('',(-26.761690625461,27.5,-28.4243433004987));
#462=CARTESIAN_POINT('',(-26.1278670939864,27.5,-28.6781337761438));
#463=CARTESIAN_POINT('',(-24.856813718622,27.5,-29.177025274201));
#464=CARTESIAN_POINT('',(-24.2195839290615,27.5,-29.4221264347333));
#465=CARTESIAN_POINT('',(-22.9413245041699,27.5,-29.9025185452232));
#466=CARTESIAN_POINT('',(-22.3002943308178,27.5,-30.1378080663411));
#467=CARTESIAN_POINT('',(-21.0142476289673,27.5,-30.5971975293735));
#468=CARTESIAN_POINT('',(-20.3692311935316,27.5,-30.8212977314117));
#469=CARTESIAN_POINT('',(-19.0762913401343,27.5,-31.256336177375));
#470=CARTESIAN_POINT('',(-18.4283771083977,27.5,-31.4673015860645));
#471=CARTESIAN_POINT('',(-17.1280636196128,27.5,-31.874881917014));
#472=CARTESIAN_POINT('',(-16.4756642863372,27.5,-32.0714965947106));
#473=CARTESIAN_POINT('',(-14.5117448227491,27.5,-32.6369304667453));
#474=CARTESIAN_POINT('',(-13.1930050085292,27.5,-32.9815100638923));
#475=CARTESIAN_POINT('',(-11.2007577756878,27.5,-33.4371656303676));
#476=CARTESIAN_POINT('',(-10.5341776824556,27.5,-33.5788718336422));
#477=CARTESIAN_POINT('',(-9.19657522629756,27.5,-33.8396423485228));
#478=CARTESIAN_POINT('',(-8.52555296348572,27.5,-33.9587071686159));
#479=CARTESIAN_POINT('',(-7.17952384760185,27.5,-34.1720839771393));
#480=CARTESIAN_POINT('',(-6.50451675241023,27.5,-34.2663944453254));
#481=CARTESIAN_POINT('',(-5.15128946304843,27.5,-34.4283683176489));
#482=CARTESIAN_POINT('',(-4.47306926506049,27.5,-34.4960316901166));
#483=CARTESIAN_POINT('',(-3.1187108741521,27.5,-34.6028897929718));
#484=CARTESIAN_POINT('',(-2.44258682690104,27.5,-34.6422626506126));
#485=CARTESIAN_POINT('',(-1.08928096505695,27.5,-34.6923327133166));
#486=CARTESIAN_POINT('',(-0.41209916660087,27.5,-34.7030303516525));
#487=CARTESIAN_POINT('',(0.941918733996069,27.5,-34.6954963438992));
#488=CARTESIAN_POINT('',(1.61875487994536,27.5,-34.6772727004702));
#489=CARTESIAN_POINT('',(2.97106504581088,27.5,-34.6123489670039));
#490=CARTESIAN_POINT('',(3.64653900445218,27.5,-34.5656476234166));
#491=CARTESIAN_POINT('',(5.28317631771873,27.5,-34.4189661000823));
#492=CARTESIAN_POINT('',(6.24308439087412,27.5,-34.3047469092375));
#493=CARTESIAN_POINT('',(8.15543073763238,27.5,-34.0251507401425));
#494=CARTESIAN_POINT('',(9.10786788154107,27.5,-33.8597661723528));
#495=CARTESIAN_POINT('',(11.0057578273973,27.5,-33.4834652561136));
#496=CARTESIAN_POINT('',(11.9511910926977,27.5,-33.2724513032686));
#497=CARTESIAN_POINT('',(13.8323781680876,27.5,-32.8114440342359));
#498=CARTESIAN_POINT('',(14.7681323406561,27.5,-32.5614521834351));
#499=CARTESIAN_POINT('',(16.6519981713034,27.5,-32.0222222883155));
#500=CARTESIAN_POINT('',(17.5998839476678,27.5,-31.7322004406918));
#501=CARTESIAN_POINT('',(19.4863693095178,27.5,-31.1232820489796));
#502=CARTESIAN_POINT('',(20.4249680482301,27.5,-30.804382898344));
#503=CARTESIAN_POINT('',(22.2883658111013,27.5,-30.1444557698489));
#504=CARTESIAN_POINT('',(23.2132128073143,27.5,-29.8035627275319));
#505=CARTESIAN_POINT('',(24.5946517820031,27.5,-29.2774659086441));
#506=CARTESIAN_POINT('',(25.0540862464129,27.5,-29.0996704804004));
#507=CARTESIAN_POINT('',(25.9711665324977,27.5,-28.7395606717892));
#508=CARTESIAN_POINT('',(26.4288124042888,27.5,-28.5572464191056));
#509=CARTESIAN_POINT('',(26.8856293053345,27.5,-28.3728755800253));
#510=B_SPLINE_CURVE_WITH_KNOTS('',3,(#448,#449,#450,#451,#452,#453,#454,#455,#456,#457,#458,
#459,#460,#461,#462,#463,#464,#465,#466,#467,#468,#469,#470,#471,#472,#473,#474,#475,#476,#477,
#478,#479,#480,#481,#482,#483,#484,#485,#486,#487,#488,#489,#490,#491,#492,#493,#494,#495,#496,
#497,#498,#499,#500,#501,#502,#503,#504,#505,#506,#507,#508,#509),.UNSPECIFIED.,.F.,.F.,(4,2,2,
2,2,2,2,2,2,2,2,2,2,2,2,2,2,2,2,2,2,2,2,2,2,2,2,2,2,2,4),(0.,2.01152483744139,4.02307175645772,
6.03496003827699,8.0468432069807,12.093617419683,16.1401806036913,18.1883662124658,
20.2365192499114,22.2849695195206,24.3333721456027,26.3773870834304,28.42143684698,
32.5079579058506,34.5520769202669,36.5961500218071,38.640348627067,40.6845496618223,
42.7157641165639,44.7469478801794,46.7775697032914,48.808280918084,51.7067063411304,
54.6055619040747,57.5106807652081,60.4156904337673,63.3889230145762,66.3624242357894,
69.3191566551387,70.7970485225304,72.2748986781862),.UNSPECIFIED.);
#511=CARTESIAN_POINT('',(0.,27.5,-34.7));
#512=VERTEX_POINT('',#511);
#513=EDGE_CURVE('E230',#445,#512,#510,.F.);
#514=ORIENTED_EDGE('',*,*,#513,.T.);
#515=EDGE_CURVE('E64',#512,#322,#510,.F.);
#516=ORIENTED_EDGE('',*,*,#515,.T.);
#517=EDGE_LOOP('',(#372,#439,#447,#514,#516));
#518=FACE_BOUND('',#517,.T.);
#519=ADVANCED_FACE('F295',(#518),#371,.T.);
#520=CARTESIAN_POINT('',(31.7542648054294,0.,-34.7));
#521=DIRECTION('',(0.866025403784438,0.5,0.));
#522=DIRECTION('',(-0.5,0.866025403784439,0.));
#523=AXIS2_PLACEMENT_3D('',#520,#521,#522);
#524=PLANE('',#523);
#525=ORIENTED_EDGE('',*,*,#446,.T.);
#526=CARTESIAN_POINT('',(15.8770169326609,27.5002,-3.58210062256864));
#527=CARTESIAN_POINT('',(16.2259892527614,26.8957622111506,-3.38063638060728));
#528=CARTESIAN_POINT('',(16.5763227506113,26.2889667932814,-3.1883143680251));
#529=CARTESIAN_POINT('',(17.2797989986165,25.0705101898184,-2.82449599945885));
#530=CARTESIAN_POINT('',(17.6329426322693,24.4588474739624,-2.65300649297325));
#531=CARTESIAN_POINT('',(18.3427291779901,23.229461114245,-2.3331549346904));
#532=CARTESIAN_POINT('',(18.6993783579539,22.6117266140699,-2.18484811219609));
#533=CARTESIAN_POINT('',(19.4151397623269,21.371991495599,-1.91455679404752));
#534=CARTESIAN_POINT('',(19.7742517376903,20.7499913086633,-1.79256967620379));
#535=CARTESIAN_POINT('',(20.4857595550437,19.5176236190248,-1.58009593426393));
#536=CARTESIAN_POINT('',(20.8381026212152,18.907347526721,-1.48890665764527));
#537=CARTESIAN_POINT('',(21.5444032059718,17.683999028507,-1.33600321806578));
#538=CARTESIAN_POINT('',(21.8983607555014,17.0709265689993,-1.27428962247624));
#539=CARTESIAN_POINT('',(22.6068704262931,15.8437518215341,-1.181895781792));
#540=CARTESIAN_POINT('',(22.9614213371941,15.2296516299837,-1.15117866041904));
#541=CARTESIAN_POINT('',(23.6708503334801,14.0008845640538,-1.12143833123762));
#542=CARTESIAN_POINT('',(24.025728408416,13.3862177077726,-1.12241414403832));
#543=CARTESIAN_POINT('',(24.6891773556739,12.2370904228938,-1.15384594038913));
#544=CARTESIAN_POINT('',(24.9977954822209,11.7025481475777,-1.18046909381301));
#545=CARTESIAN_POINT('',(25.6142949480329,10.6347397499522,-1.25717911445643));
#546=CARTESIAN_POINT('',(25.9221762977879,10.1014736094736,-1.30726564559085));
#547=CARTESIAN_POINT('',(26.5370884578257,9.03641450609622,-1.43003437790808));
#548=CARTESIAN_POINT('',(26.8441182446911,8.50462331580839,-1.50273701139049));
#549=CARTESIAN_POINT('',(27.4567077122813,7.44358723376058,-1.66945124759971));
#550=CARTESIAN_POINT('',(27.7622673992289,6.9143423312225,-1.76346276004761));
#551=CARTESIAN_POINT('',(28.6898814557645,5.3076676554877,-2.07987326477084));
#552=CARTESIAN_POINT('',(29.3093003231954,4.23480270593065,-2.33383899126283));
#553=CARTESIAN_POINT('',(30.2315881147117,2.63735339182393,-2.76620358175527));
#554=CARTESIAN_POINT('',(30.5376130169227,2.10730271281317,-2.91873886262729));
#555=CARTESIAN_POINT('',(31.1475461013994,1.0508676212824,-3.23925171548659));
#556=CARTESIAN_POINT('',(31.4514548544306,0.524482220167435,-3.40722493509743));
#557=CARTESIAN_POINT('',(31.7543802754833,-0.000199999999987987,-3.58210062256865));
#558=B_SPLINE_CURVE_WITH_KNOTS('',3,(#526,#527,#528,#529,#530,#531,#532,#533,#534,#535,#536,
#537,#538,#539,#540,#541,#542,#543,#544,#545,#546,#547,#548,#549,#550,#551,#552,#553,#554,#555,
#556,#557),.UNSPECIFIED.,.F.,.F.,(4,2,2,2,2,2,2,2,2,2,2,2,2,2,2,4),(0.,2.17937596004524,
4.35946654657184,6.54467421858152,8.72966408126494,10.8607692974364,12.9919155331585,
15.120523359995,17.2490654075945,19.1020483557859,20.9550047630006,22.8096400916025,
24.6642675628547,28.4552152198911,30.3473870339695,32.2390270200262),.UNSPECIFIED.);
#559=CARTESIAN_POINT('',(31.7542648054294,0.,-3.58203395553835));
#560=VERTEX_POINT('',#559);
#561=EDGE_CURVE('E281',#437,#560,#558,.T.);
#562=ORIENTED_EDGE('',*,*,#561,.T.);
#563=DIRECTION('',(0.,0.,1.));
#564=VECTOR('',#563,1.);
#565=CARTESIAN_POINT('',(31.7542648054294,0.,-34.7));
#566=LINE('',#565,#564);
#567=CARTESIAN_POINT('',(31.7542648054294,0.,-32.2437990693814));
#568=VERTEX_POINT('',#567);
#569=EDGE_CURVE('E148',#568,#560,#566,.T.);
#570=ORIENTED_EDGE('',*,*,#569,.F.);
#571=CARTESIAN_POINT('',(31.7543802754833,-0.000199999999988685,-32.2437324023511));
#572=CARTESIAN_POINT('',(31.4054079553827,0.604237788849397,-32.4451966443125));
#573=CARTESIAN_POINT('',(31.0550744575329,1.21103320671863,-32.6375186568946));
#574=CARTESIAN_POINT('',(30.3515982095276,2.42948981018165,-33.0013370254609));
#575=CARTESIAN_POINT('',(29.9984545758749,3.04115252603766,-33.1728265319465));
#576=CARTESIAN_POINT('',(29.288668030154,4.27053888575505,-33.4926780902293));
#577=CARTESIAN_POINT('',(28.9320188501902,4.88827338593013,-33.6409849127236));
#578=CARTESIAN_POINT('',(28.2162574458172,6.12800850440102,-33.9112762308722));
#579=CARTESIAN_POINT('',(27.8571454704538,6.75000869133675,-34.0332633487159));
#580=CARTESIAN_POINT('',(27.1456376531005,7.98237638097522,-34.2457370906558));
#581=CARTESIAN_POINT('',(26.7932945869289,8.59265247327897,-34.3369263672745));
#582=CARTESIAN_POINT('',(26.0869940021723,9.81600097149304,-34.489829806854));
#583=CARTESIAN_POINT('',(25.7330364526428,10.4290734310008,-34.5515434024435));
#584=CARTESIAN_POINT('',(25.024526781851,11.6562481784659,-34.6439372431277));
#585=CARTESIAN_POINT('',(24.66997587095,12.2703483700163,-34.6746543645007));
#586=CARTESIAN_POINT('',(23.960546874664,13.4991154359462,-34.7043946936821));
#587=CARTESIAN_POINT('',(23.6056687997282,14.1137822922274,-34.7034188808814));
#588=CARTESIAN_POINT('',(22.9422198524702,15.2629095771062,-34.6719870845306));
#589=CARTESIAN_POINT('',(22.6336017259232,15.7974518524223,-34.6453639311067));
#590=CARTESIAN_POINT('',(22.0171022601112,16.8652602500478,-34.5686539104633));
#591=CARTESIAN_POINT('',(21.7092209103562,17.3985263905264,-34.5185673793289));
#592=CARTESIAN_POINT('',(21.0943087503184,18.4635854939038,-34.3957986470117));
#593=CARTESIAN_POINT('',(20.787278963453,18.9953766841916,-34.3230960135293));
#594=CARTESIAN_POINT('',(20.1746894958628,20.0564127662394,-34.15638177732));
#595=CARTESIAN_POINT('',(19.8691298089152,20.5856576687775,-34.0623702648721));
#596=CARTESIAN_POINT('',(18.9415157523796,22.1923323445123,-33.7459597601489));
#597=CARTESIAN_POINT('',(18.3220968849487,23.2651972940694,-33.4919940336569));
#598=CARTESIAN_POINT('',(17.3998090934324,24.8626466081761,-33.0596294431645));
#599=CARTESIAN_POINT('',(17.0937841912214,25.3926972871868,-32.9070941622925));
#600=CARTESIAN_POINT('',(16.4838511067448,26.4491323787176,-32.5865813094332));
#601=CARTESIAN_POINT('',(16.1799423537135,26.9755177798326,-32.4186080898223));
#602=CARTESIAN_POINT('',(15.8770169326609,27.5002,-32.2437324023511));
#603=B_SPLINE_CURVE_WITH_KNOTS('',3,(#571,#572,#573,#574,#575,#576,#577,#578,#579,#580,#581,
#582,#583,#584,#585,#586,#587,#588,#589,#590,#591,#592,#593,#594,#595,#596,#597,#598,#599,#600,
#601,#602),.UNSPECIFIED.,.F.,.F.,(4,2,2,2,2,2,2,2,2,2,2,2,2,2,2,4),(0.,2.17937596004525,
4.35946654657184,6.54467421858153,8.72966408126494,10.8607692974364,12.9919155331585,
15.120523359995,17.2490654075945,19.1020483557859,20.9550047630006,22.8096400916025,
24.6642675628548,28.4552152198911,30.3473870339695,32.2390270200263),.UNSPECIFIED.);
#604=CARTESIAN_POINT('',(23.815698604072,13.75,-34.7));
#605=VERTEX_POINT('',#604);
#606=EDGE_CURVE('E184',#568,#605,#603,.T.);
#607=ORIENTED_EDGE('',*,*,#606,.T.);
#608=EDGE_CURVE('E194',#605,#445,#603,.T.);
#609=ORIENTED_EDGE('',*,*,#608,.T.);
#610=EDGE_LOOP('',(#525,#562,#570,#607,#609));
#611=FACE_BOUND('',#610,.T.);
#612=ADVANCED_FACE('F300',(#611),#524,.T.);
#613=CARTESIAN_POINT('',(15.8771324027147,-27.5,-34.7));
#614=DIRECTION('',(0.866025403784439,-0.5,0.));
#615=DIRECTION('',(0.5,0.866025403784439,0.));
#616=AXIS2_PLACEMENT_3D('',#613,#614,#615);
#617=PLANE('',#616);
#618=ORIENTED_EDGE('',*,*,#569,.T.);
#619=CARTESIAN_POINT('',(31.7543802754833,0.000200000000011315,-3.58210062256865));
#620=CARTESIAN_POINT('',(31.4054079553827,-0.604237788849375,-3.38063638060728));
#621=CARTESIAN_POINT('',(31.0550744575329,-1.21103320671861,-3.18831436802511));
#622=CARTESIAN_POINT('',(30.3515982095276,-2.42948981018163,-2.82449599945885));
#623=CARTESIAN_POINT('',(29.9984545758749,-3.04115252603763,-2.65300649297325));
#624=CARTESIAN_POINT('',(29.288668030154,-4.27053888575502,-2.3331549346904));
#625=CARTESIAN_POINT('',(28.9320188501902,-4.88827338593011,-2.18484811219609));
#626=CARTESIAN_POINT('',(28.2162574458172,-6.128008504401,-1.91455679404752));
#627=CARTESIAN_POINT('',(27.8571454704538,-6.75000869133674,-1.79256967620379));
#628=CARTESIAN_POINT('',(27.1456376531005,-7.9823763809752,-1.58009593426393));
#629=CARTESIAN_POINT('',(26.7932945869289,-8.59265247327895,-1.48890665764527));
#630=CARTESIAN_POINT('',(26.0869940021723,-9.81600097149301,-1.33600321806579));
#631=CARTESIAN_POINT('',(25.7330364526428,-10.4290734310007,-1.27428962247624));
#632=CARTESIAN_POINT('',(25.024526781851,-11.6562481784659,-1.181895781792));
#633=CARTESIAN_POINT('',(24.66997587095,-12.2703483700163,-1.15117866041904));
#634=CARTESIAN_POINT('',(23.960546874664,-13.4991154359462,-1.12143833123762));
#635=CARTESIAN_POINT('',(23.6056687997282,-14.1137822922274,-1.12241414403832));
#636=CARTESIAN_POINT('',(22.9422198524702,-15.2629095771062,-1.15384594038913));
#637=CARTESIAN_POINT('',(22.6336017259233,-15.7974518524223,-1.180469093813));
#638=CARTESIAN_POINT('',(22.0171022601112,-16.8652602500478,-1.25717911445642));
#639=CARTESIAN_POINT('',(21.7092209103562,-17.3985263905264,-1.30726564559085));
#640=CARTESIAN_POINT('',(21.0943087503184,-18.4635854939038,-1.43003437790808));
#641=CARTESIAN_POINT('',(20.787278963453,-18.9953766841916,-1.50273701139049));
#642=CARTESIAN_POINT('',(20.1746894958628,-20.0564127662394,-1.6694512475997));
#643=CARTESIAN_POINT('',(19.8691298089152,-20.5856576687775,-1.76346276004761));
#644=CARTESIAN_POINT('',(18.9415157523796,-22.1923323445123,-2.07987326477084));
#645=CARTESIAN_POINT('',(18.3220968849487,-23.2651972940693,-2.33383899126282));
#646=CARTESIAN_POINT('',(17.3998090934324,-24.8626466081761,-2.76620358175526));
#647=CARTESIAN_POINT('',(17.0937841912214,-25.3926972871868,-2.91873886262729));
#648=CARTESIAN_POINT('',(16.4838511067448,-26.4491323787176,-3.23925171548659));
#649=CARTESIAN_POINT('',(16.1799423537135,-26.9755177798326,-3.40722493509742));
#650=CARTESIAN_POINT('',(15.8770169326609,-27.5002,-3.58210062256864));
#651=B_SPLINE_CURVE_WITH_KNOTS('',3,(#619,#620,#621,#622,#623,#624,#625,#626,#627,#628,#629,
#630,#631,#632,#633,#634,#635,#636,#637,#638,#639,#640,#641,#642,#643,#644,#645,#646,#647,#648,
#649,#650),.UNSPECIFIED.,.F.,.F.,(4,2,2,2,2,2,2,2,2,2,2,2,2,2,2,4),(0.,2.17937596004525,
4.35946654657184,6.54467421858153,8.72966408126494,10.8607692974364,12.9919155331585,
15.120523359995,17.2490654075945,19.1020483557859,20.9550047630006,22.8096400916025,
24.6642675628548,28.4552152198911,30.3473870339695,32.2390270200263),.UNSPECIFIED.);
#652=EDGE_CURVE('E273',#560,#31,#651,.T.);
#653=ORIENTED_EDGE('',*,*,#652,.T.);
#654=ORIENTED_EDGE('',*,*,#32,.F.);
#655=CARTESIAN_POINT('',(15.8770169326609,-27.5002,-32.2437324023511));
#656=CARTESIAN_POINT('',(16.2259892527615,-26.8957622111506,-32.4451966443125));
#657=CARTESIAN_POINT('',(16.5763227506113,-26.2889667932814,-32.6375186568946));
#658=CARTESIAN_POINT('',(17.2797989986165,-25.0705101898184,-33.0013370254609));
#659=CARTESIAN_POINT('',(17.6329426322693,-24.4588474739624,-33.1728265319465));
#660=CARTESIAN_POINT('',(18.3427291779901,-23.229461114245,-33.4926780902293));
#661=CARTESIAN_POINT('',(18.6993783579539,-22.6117266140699,-33.6409849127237));
#662=CARTESIAN_POINT('',(19.4151397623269,-21.371991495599,-33.9112762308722));
#663=CARTESIAN_POINT('',(19.7742517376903,-20.7499913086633,-34.0332633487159));
#664=CARTESIAN_POINT('',(20.4857595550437,-19.5176236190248,-34.2457370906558));
#665=CARTESIAN_POINT('',(20.8381026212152,-18.907347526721,-34.3369263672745));
#666=CARTESIAN_POINT('',(21.5444032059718,-17.683999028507,-34.489829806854));
#667=CARTESIAN_POINT('',(21.8983607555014,-17.0709265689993,-34.5515434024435));
#668=CARTESIAN_POINT('',(22.6068704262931,-15.8437518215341,-34.6439372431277));
#669=CARTESIAN_POINT('',(22.9614213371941,-15.2296516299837,-34.6746543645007));
#670=CARTESIAN_POINT('',(23.6708503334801,-14.0008845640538,-34.7043946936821));
#671=CARTESIAN_POINT('',(24.025728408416,-13.3862177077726,-34.7034188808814));
#672=CARTESIAN_POINT('',(24.6891773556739,-12.2370904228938,-34.6719870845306));
#673=CARTESIAN_POINT('',(24.9977954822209,-11.7025481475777,-34.6453639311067));
#674=CARTESIAN_POINT('',(25.6142949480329,-10.6347397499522,-34.5686539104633));
#675=CARTESIAN_POINT('',(25.9221762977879,-10.1014736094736,-34.5185673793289));
#676=CARTESIAN_POINT('',(26.5370884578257,-9.0364145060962,-34.3957986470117));
#677=CARTESIAN_POINT('',(26.8441182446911,-8.50462331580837,-34.3230960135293));
#678=CARTESIAN_POINT('',(27.4567077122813,-7.44358723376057,-34.15638177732));
#679=CARTESIAN_POINT('',(27.7622673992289,-6.91434233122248,-34.0623702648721));
#680=CARTESIAN_POINT('',(28.6898814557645,-5.30766765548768,-33.7459597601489));
#681=CARTESIAN_POINT('',(29.3093003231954,-4.23480270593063,-33.4919940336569));
#682=CARTESIAN_POINT('',(30.2315881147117,-2.63735339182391,-33.0596294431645));
#683=CARTESIAN_POINT('',(30.5376130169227,-2.10730271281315,-32.9070941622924));
#684=CARTESIAN_POINT('',(31.1475461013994,-1.05086762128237,-32.5865813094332));
#685=CARTESIAN_POINT('',(31.4514548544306,-0.524482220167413,-32.4186080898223));
#686=CARTESIAN_POINT('',(31.7543802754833,0.000200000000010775,-32.2437324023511));
#687=B_SPLINE_CURVE_WITH_KNOTS('',3,(#655,#656,#657,#658,#659,#660,#661,#662,#663,#664,#665,
#666,#667,#668,#669,#670,#671,#672,#673,#674,#675,#676,#677,#678,#679,#680,#681,#682,#683,#684,
#685,#686),.UNSPECIFIED.,.F.,.F.,(4,2,2,2,2,2,2,2,2,2,2,2,2,2,2,4),(0.,2.17937596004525,
4.35946654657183,6.54467421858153,8.72966408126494,10.8607692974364,12.9919155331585,
15.120523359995,17.2490654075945,19.1020483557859,20.9550047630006,22.8096400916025,
24.6642675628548,28.4552152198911,30.3473870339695,32.2390270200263),.UNSPECIFIED.);
#688=CARTESIAN_POINT('',(23.8156986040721,-13.75,-34.7));
#689=VERTEX_POINT('',#688);
#690=EDGE_CURVE('E173',#29,#689,#687,.T.);
#691=ORIENTED_EDGE('',*,*,#690,.T.);
#692=EDGE_CURVE('E181',#689,#568,#687,.T.);
#693=ORIENTED_EDGE('',*,*,#692,.T.);
#694=EDGE_LOOP('',(#618,#653,#654,#691,#693));
#695=FACE_BOUND('',#694,.T.);
#696=ADVANCED_FACE('F195',(#695),#617,.T.);
#697=CARTESIAN_POINT('',(15.8771324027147,-27.5,0.));
#698=DIRECTION('',(0.,0.,1.));
#699=DIRECTION('',(1.,0.,0.));
#700=AXIS2_PLACEMENT_3D('',#697,#698,#699);
#701=PLANE('',#700);
#702=CARTESIAN_POINT('',(0.,0.,0.));
#703=DIRECTION('',(0.,0.,1.));
#704=DIRECTION('',(1.,0.,0.));
#705=AXIS2_PLACEMENT_3D('',#702,#703,#704);
#706=CIRCLE('',#705,18.6566666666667);
#707=CARTESIAN_POINT('',(18.6566666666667,0.,0.));
#708=VERTEX_POINT('',#707);
#709=EDGE_CURVE('E11',#708,#708,#706,.F.);
#710=ORIENTED_EDGE('',*,*,#709,.T.);
#711=EDGE_LOOP('',(#710));
#712=FACE_BOUND('',#711,.T.);
#713=CARTESIAN_POINT('',(0.,0.,0.));
#714=DIRECTION('',(0.,0.,-1.));
#715=DIRECTION('',(-1.,0.,0.));
#716=AXIS2_PLACEMENT_3D('',#713,#714,#715);
#717=CIRCLE('',#716,25.55);
#718=CARTESIAN_POINT('',(-25.55,0.,0.));
#719=VERTEX_POINT('',#718);
#720=EDGE_CURVE('E340',#719,#719,#717,.T.);
#721=ORIENTED_EDGE('',*,*,#720,.F.);
#722=EDGE_LOOP('',(#721));
#723=FACE_BOUND('',#722,.T.);
#724=ADVANCED_FACE('F252',(#712,#723),#701,.T.);
#725=CARTESIAN_POINT('',(15.8771324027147,-27.5,-34.7));
#726=DIRECTION('',(0.,0.,1.));
#727=DIRECTION('',(1.,0.,0.));
#728=AXIS2_PLACEMENT_3D('',#725,#726,#727);
#729=PLANE('',#728);
#730=CARTESIAN_POINT('',(0.,0.,-34.7));
#731=DIRECTION('',(0.,0.,1.));
#732=DIRECTION('',(1.,0.,0.));
#733=AXIS2_PLACEMENT_3D('',#730,#731,#732);
#734=CIRCLE('',#733,19.45);
#735=CARTESIAN_POINT('',(19.45,0.,-34.7));
#736=VERTEX_POINT('',#735);
#737=EDGE_CURVE('E331',#736,#736,#734,.T.);
#738=ORIENTED_EDGE('',*,*,#737,.T.);
#739=EDGE_LOOP('',(#738));
#740=FACE_BOUND('',#739,.T.);
#741=CARTESIAN_POINT('',(0.,0.,-34.7));
#742=DIRECTION('',(0.,0.,1.));
#743=DIRECTION('',(1.,0.,0.));
#744=AXIS2_PLACEMENT_3D('',#741,#742,#743);
#745=CIRCLE('',#744,27.5);
#746=EDGE_CURVE('E189',#605,#512,#745,.T.);
#747=ORIENTED_EDGE('',*,*,#746,.F.);
#748=CARTESIAN_POINT('',(0.,0.,-34.7));
#749=DIRECTION('',(0.,0.,1.));
#750=DIRECTION('',(1.,0.,0.));
#751=AXIS2_PLACEMENT_3D('',#748,#749,#750);
#752=CIRCLE('',#751,27.5);
#753=EDGE_CURVE('E137',#689,#605,#752,.T.);
#754=ORIENTED_EDGE('',*,*,#753,.F.);
#755=EDGE_CURVE('E151',#173,#689,#752,.T.);
#756=ORIENTED_EDGE('',*,*,#755,.F.);
#757=EDGE_CURVE('E161',#266,#173,#752,.T.);
#758=ORIENTED_EDGE('',*,*,#757,.F.);
#759=EDGE_CURVE('E160',#359,#266,#752,.T.);
#760=ORIENTED_EDGE('',*,*,#759,.F.);
#761=EDGE_CURVE('E153',#512,#359,#752,.T.);
#762=ORIENTED_EDGE('',*,*,#761,.F.);
#763=EDGE_LOOP('',(#747,#754,#756,#758,#760,#762));
#764=FACE_BOUND('',#763,.T.);
#765=ADVANCED_FACE('F188',(#740,#764),#729,.F.);
#766=CARTESIAN_POINT('',(0.,0.,-34.7));
#767=DIRECTION('',(0.,0.,1.));
#768=DIRECTION('',(1.,0.,0.));
#769=AXIS2_PLACEMENT_3D('',#766,#767,#768);
#770=CYLINDRICAL_SURFACE('',#769,17.5);
#771=CARTESIAN_POINT('',(0.,0.,-1.15666666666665));
#772=DIRECTION('',(0.,0.,1.));
#773=DIRECTION('',(1.,0.,0.));
#774=AXIS2_PLACEMENT_3D('',#771,#772,#773);
#775=CIRCLE('',#774,17.5);
#776=CARTESIAN_POINT('',(17.5,0.,-1.15666666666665));
#777=VERTEX_POINT('',#776);
#778=EDGE_CURVE('E47',#777,#777,#775,.T.);
#779=ORIENTED_EDGE('',*,*,#778,.T.);
#780=EDGE_LOOP('',(#779));
#781=FACE_BOUND('',#780,.T.);
#782=CARTESIAN_POINT('',(0.,0.,-33.5741669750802));
#783=DIRECTION('',(0.,0.,1.));
#784=DIRECTION('',(1.,0.,0.));
#785=AXIS2_PLACEMENT_3D('',#782,#783,#784);
#786=CIRCLE('',#785,17.5);
#787=CARTESIAN_POINT('',(17.5,0.,-33.5741669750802));
#788=VERTEX_POINT('',#787);
#789=EDGE_CURVE('E451',#788,#788,#786,.T.);
#790=ORIENTED_EDGE('',*,*,#789,.F.);
#791=EDGE_LOOP('',(#790));
#792=FACE_BOUND('',#791,.T.);
#793=ADVANCED_FACE('F214',(#781,#792),#770,.F.);
#794=CARTESIAN_POINT('',(0.,0.,-32.2437990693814));
#795=DIRECTION('',(0.,0.,1.));
#796=DIRECTION('',(1.,0.,0.));
#797=AXIS2_PLACEMENT_3D('',#794,#795,#796);
#798=CONICAL_SURFACE('',#797,31.7542648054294,1.0471975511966);
#799=ORIENTED_EDGE('',*,*,#692,.F.);
#800=ORIENTED_EDGE('',*,*,#753,.T.);
#801=ORIENTED_EDGE('',*,*,#606,.F.);
#802=EDGE_LOOP('',(#799,#800,#801));
#803=FACE_BOUND('',#802,.T.);
#804=ADVANCED_FACE('F185',(#803),#798,.T.);
#805=ORIENTED_EDGE('',*,*,#755,.T.);
#806=ORIENTED_EDGE('',*,*,#690,.F.);
#807=ORIENTED_EDGE('',*,*,#176,.F.);
#808=EDGE_LOOP('',(#805,#806,#807));
#809=FACE_BOUND('',#808,.T.);
#810=ADVANCED_FACE('F171',(#809),#798,.T.);
#811=ORIENTED_EDGE('',*,*,#757,.T.);
#812=ORIENTED_EDGE('',*,*,#174,.F.);
#813=ORIENTED_EDGE('',*,*,#269,.F.);
#814=EDGE_LOOP('',(#811,#812,#813));
#815=FACE_BOUND('',#814,.T.);
#816=ADVANCED_FACE('F318',(#815),#798,.T.);
#817=ORIENTED_EDGE('',*,*,#759,.T.);
#818=ORIENTED_EDGE('',*,*,#267,.F.);
#819=ORIENTED_EDGE('',*,*,#362,.F.);
#820=EDGE_LOOP('',(#817,#818,#819));
#821=FACE_BOUND('',#820,.T.);
#822=ADVANCED_FACE('F319',(#821),#798,.T.);
#823=ORIENTED_EDGE('',*,*,#515,.F.);
#824=ORIENTED_EDGE('',*,*,#761,.T.);
#825=ORIENTED_EDGE('',*,*,#360,.F.);
#826=EDGE_LOOP('',(#823,#824,#825));
#827=FACE_BOUND('',#826,.T.);
#828=ADVANCED_FACE('F212',(#827),#798,.T.);
#829=ORIENTED_EDGE('',*,*,#608,.F.);
#830=ORIENTED_EDGE('',*,*,#746,.T.);
#831=ORIENTED_EDGE('',*,*,#513,.F.);
#832=EDGE_LOOP('',(#829,#830,#831));
#833=FACE_BOUND('',#832,.T.);
#834=ADVANCED_FACE('F322',(#833),#798,.T.);
#835=CARTESIAN_POINT('',(0.,0.,-33.5741669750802));
#836=DIRECTION('',(0.,0.,-1.));
#837=DIRECTION('',(-1.,0.,0.));
#838=AXIS2_PLACEMENT_3D('',#835,#836,#837);
#839=CONICAL_SURFACE('',#838,17.5,1.0471975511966);
#840=ORIENTED_EDGE('',*,*,#737,.F.);
#841=EDGE_LOOP('',(#840));
#842=FACE_BOUND('',#841,.T.);
#843=ORIENTED_EDGE('',*,*,#789,.T.);
#844=EDGE_LOOP('',(#843));
#845=FACE_BOUND('',#844,.T.);
#846=ADVANCED_FACE('F217',(#842,#845),#839,.F.);
#847=CARTESIAN_POINT('',(0.,0.,-3.58203395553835));
#848=DIRECTION('',(0.,0.,-1.));
#849=DIRECTION('',(-1.,0.,0.));
#850=AXIS2_PLACEMENT_3D('',#847,#848,#849);
#851=CONICAL_SURFACE('',#850,31.7542648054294,1.0471975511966);
#852=ORIENTED_EDGE('',*,*,#720,.T.);
#853=EDGE_LOOP('',(#852));
#854=FACE_BOUND('',#853,.T.);
#855=ORIENTED_EDGE('',*,*,#652,.F.);
#856=ORIENTED_EDGE('',*,*,#561,.F.);
#857=ORIENTED_EDGE('',*,*,#438,.F.);
#858=ORIENTED_EDGE('',*,*,#315,.F.);
#859=ORIENTED_EDGE('',*,*,#222,.F.);
#860=ORIENTED_EDGE('',*,*,#99,.F.);
#861=EDGE_LOOP('',(#855,#856,#857,#858,#859,#860));
#862=FACE_BOUND('',#861,.T.);
#863=ADVANCED_FACE('F113',(#854,#862),#851,.T.);
#864=CARTESIAN_POINT('',(0.,0.,-1.15666666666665));
#865=DIRECTION('',(0.,0.,1.));
#866=DIRECTION('',(1.,0.,0.));
#867=AXIS2_PLACEMENT_3D('',#864,#865,#866);
#868=CONICAL_SURFACE('',#867,17.5,0.785398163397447);
#869=ORIENTED_EDGE('',*,*,#709,.F.);
#870=EDGE_LOOP('',(#869));
#871=FACE_BOUND('',#870,.T.);
#872=ORIENTED_EDGE('',*,*,#778,.F.);
#873=EDGE_LOOP('',(#872));
#874=FACE_BOUND('',#873,.T.);
#875=ADVANCED_FACE('F43',(#871,#874),#868,.F.);
#876=CLOSED_SHELL('',(#180,#273,#366,#519,#612,#696,#724,#765,#793,#804,#810,#816,#822,#828,
#834,#846,#863,#875));
#877=MANIFOLD_SOLID_BREP('B2',#876);
#878=ADVANCED_BREP_SHAPE_REPRESENTATION('',(#18,#877),#14);
#879=SHAPE_DEFINITION_REPRESENTATION(#9,#878);
ENDSEC;
END-ISO-10303-21;
